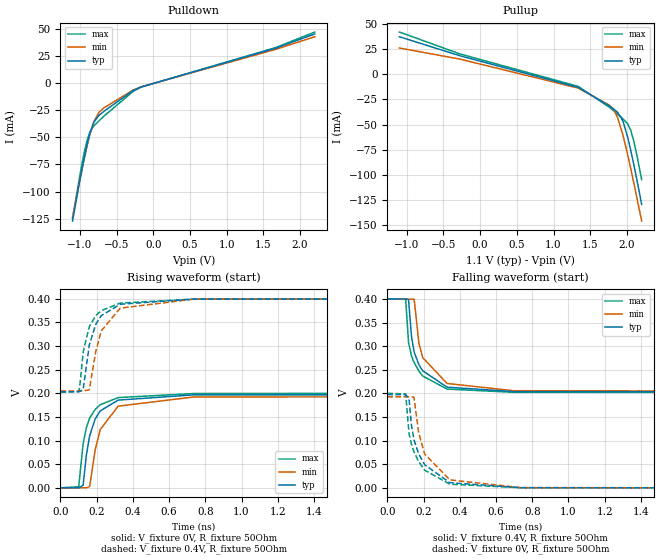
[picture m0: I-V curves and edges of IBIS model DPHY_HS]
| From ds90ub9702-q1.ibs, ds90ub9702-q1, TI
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|  DPHY_HS Tx Model
[Model]   DPHY_HS
Model_type   Output
Polarity   Non-Inverting
Vmeas = 0.2
Vref = 0.2
Cref = 1pF
Rref = 50
|   typ   min   max
C_comp   2.65pF   2.56pF   2.78pF
[Voltage Range]   1.1   1.045   1.155
[Temperature Range]   27   105   -40
[Pullup Reference]   1.1   1.045   1.155
[Pulldown Reference]   0   -0   0
[Power Clamp Reference]   1.1   1.045   1.155
[GND Clamp Reference]   0   0   0
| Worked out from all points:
|   slope of the pulldown table from 0 to 0.165 V, typ, clamps not added: 51.7 ohm
|   slope of the pullup table from 0 to 0.165 V, typ, clamps not added: 52.5 ohm
|   falling waveform, V_fixture 0.4V, R_fixture 50Ohm: 20-80 % time 79.1ps typ, 85.4ps min, 77.5ps max; typ from 0.4 V to 0.204 V
|   rising waveform, V_fixture 0V, R_fixture 50Ohm: 20-80 % time 75.7ps typ, 86ps min, 69.6ps max; typ from 0 V to 0.197 V
|   rising waveform, V_fixture 0.4V, R_fixture 50Ohm: 20-80 % time 81.7ps typ, 90.4ps min, 74.3ps max; typ from 0.204 V to 0.4 V
|   falling waveform, V_fixture 0V, R_fixture 50Ohm: 20-80 % time 98.2ps typ, 101ps min, 92.3ps max; typ from 0.197 V to 0 V
[Pulldown]
|   Voltage   I(typ)   I(min)   I(max)
-1.1V     -127.2mA   -123.8mA   -124.9mA
-994.4mV  -87.45mA   -86.96mA   -82.68mA
-948.2mV  -71.4mA    -71.86mA   -66.26mA
-902mV    -56.72mA   -57.79mA   -52.58mA
-862.4mV  -45.97mA   -47mA      -44.71mA
-809.6mV  -35.93mA   -35.5mA    -39.38mA
-740.3mV  -29.76mA   -26.9mA    -34.72mA
-674.3mV  -26.03mA   -22.85mA   -30.52mA
-275mV    -6.806mA   -6.299mA   -7.514mA
-169.4mV  -3.519mA   -3.433mA   -3.633mA
1.669V    32.36mA    31.28mA    32.93mA
2.2V      45.51mA    42.93mA    47.25mA
[Pullup]
|   Voltage   I(typ)   I(min)   I(max)
-1.1V     37.66mA    26.43mA    42.38mA
-275mV    18.65mA    15.32mA    20.51mA
1.335V    -12.88mA   -13.6mA    -11.92mA
1.761V    -31.45mA   -30.67mA   -32.76mA
1.824V    -34.77mA   -35.68mA   -36.61mA
1.873V    -37.83mA   -43.23mA   -39.69mA
1.946V    -46.7mA    -60.8mA    -44.3mA
2.012V    -63.19mA   -80.84mA   -49.56mA
2.051V    -75.66mA   -93.88mA   -55.78mA
2.091V    -89.21mA   -107.4mA   -65.99mA
2.137V    -105.9mA   -123.7mA   -81.3mA
2.2V      -129.8mA   -146.4mA   -105mA
[Ramp]
R_load = 50
|   typ   min   max
dV/dt_r   0.1183/7.52153e-11   0.115636/8.53108e-11   0.120039/6.91429e-11
dV/dt_f   0.117884/7.91703e-11   0.116867/8.53635e-11   0.118798/7.75972e-11
[Falling Waveform]
V_fixture = 0.4V
V_fixture_min = 0.4V
V_fixture_max = 0.4V
R_fixture = 50Ohm
C_fixture = 0F
|   Time   V(typ)   V(min)   V(max)
0s        400mV      399.9mV    400mV
101.3ps   400.1mV    399.6mV    399mV
117.2ps   398.5mV    399.5mV    307.6mV
133.2ps   321.8mV    399.5mV    279.7mV
148.1ps   287.7mV    399.4mV    265.2mV
174.2ps   260.8mV    307.1mV    247.4mV
195.2ps   247.9mV    275.8mV    236.9mV
330ps     213.2mV    221mV      209.1mV
699.5ps   203.8mV    205.6mV    202.3mV
2.4ns     203.5mV    205.1mV    202mV
[Rising Waveform]
V_fixture = 0V
V_fixture_min = 0V
V_fixture_max = 0V
R_fixture = 50Ohm
C_fixture = 0F
|   Time   V(typ)   V(min)   V(max)
0s        42.39uV    84.89uV    57.16uV
100.8ps   -37.34uV   25.25uV    2.25mV
124.9ps   5.327mV    10.96uV    92.54mV
143.4ps   70.35mV    21.21uV    128.1mV
161.3ps   110.2mV    2.749mV    147.7mV
192.1ps   146mV      81.23mV    166.1mV
220.3ps   163.1mV    123.8mV    176mV
318.8ps   185.7mV    172.9mV    191mV
735.6ps   196.8mV    192.3mV    199.6mV
2.4ns     197.2mV    192.8mV    200.1mV
[Rising Waveform]
V_fixture = 0.4V
V_fixture_min = 0.4V
V_fixture_max = 0.4V
R_fixture = 50Ohm
C_fixture = 0F
|   Time   V(typ)   V(min)   V(max)
0s        203.5mV    205.1mV    202mV
100.4ps   203.5mV    205.1mV    204mV
105.7ps   203.5mV    205.1mV    211.3mV
125.8ps   209.3mV    205.1mV    288.1mV
159.1ps   302.2mV    207.5mV    341.2mV
195.2ps   346.4mV    289mV      364.6mV
225.6ps   364.6mV    332.2mV    375.1mV
330ps     388.6mV    380.4mV    391.1mV
735.6ps   399.6mV    399.4mV    399.5mV
2.4ns     400mV      399.9mV    400mV
[Falling Waveform]
|Gnd
V_fixture = 0V
V_fixture_min = 0V
V_fixture_max = 0V
R_fixture = 50Ohm
C_fixture = 0F
|   Time   V(typ)   V(min)   V(max)
0s        197.2mV    192.8mV    200.1mV
101.3ps   197.3mV    192.9mV    198.8mV
120ps     188.2mV    192.9mV    114.7mV
132.5ps   134.8mV    192.8mV    93.33mV
147ps     102.3mV    191.8mV    76.54mV
173.1ps   72.02mV    116.9mV    55.43mV
206.4ps   48.85mV    71.5mV     37.43mV
344.9ps   11.07mV    16.96mV    7.82mV
735.6ps   346.2uV    498.3uV    314.1uV
2.4ns     42.48uV    84.94uV    57.48uV
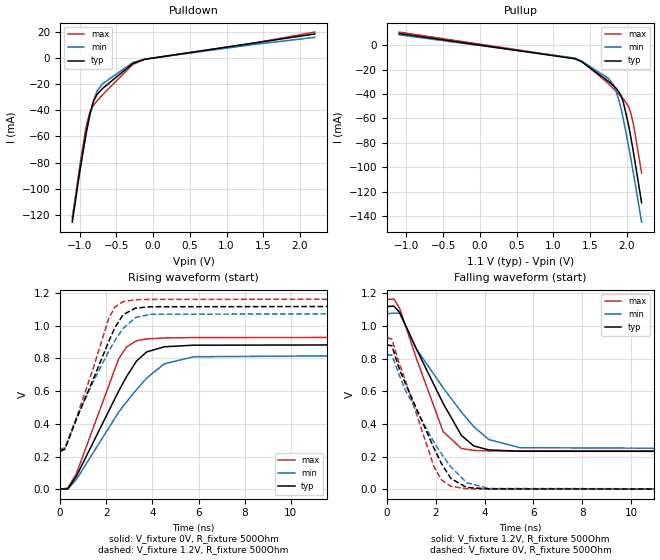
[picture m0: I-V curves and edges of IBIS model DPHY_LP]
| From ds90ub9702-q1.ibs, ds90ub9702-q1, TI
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|  DPHY_LP Tx Model - note: the diff cell line in IBIS needs to be commented out to use this model
[Model]   DPHY_LP
Model_type   Output
Polarity   Non-Inverting
Vmeas = 0.5
Vref = 0
Cref = 1pF
Rref = 100000
|   typ   min   max
C_comp   2.65pF   2.56pF   2.78pF
[Voltage Range]   1.1   1.045   1.155
[Temperature Range]   27   105   -40
[Pullup Reference]   1.1   1.045   1.155
[Pulldown Reference]   0   -0   0
[Power Clamp Reference]   1.1   1.045   1.155
[GND Clamp Reference]   0   0   0
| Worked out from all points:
|   slope of the pulldown table from 0 to 0.165 V, typ, clamps not added: 119 ohm
|   slope of the pullup table from 0 to 0.165 V, typ, clamps not added: 122 ohm
|   falling waveform, V_fixture 1.2V, R_fixture 500Ohm: 20-80 % time 1.75ns typ, 2.37ns min, 1.28ns max; typ from 1.12 V to 0.231 V
|   rising waveform, V_fixture 0V, R_fixture 500Ohm: 20-80 % time 1.9ns typ, 2.52ns min, 1.4ns max; typ from 0.001 V to 0.884 V
|   rising waveform, V_fixture 1.2V, R_fixture 500Ohm: 20-80 % time 1.58ns typ, 1.74ns min, 1.29ns max; typ from 0.231 V to 1.12 V
|   falling waveform, V_fixture 0V, R_fixture 500Ohm: 20-80 % time 1.58ns typ, 1.88ns min, 1.24ns max; typ from 0.884 V to 0 V
[Pulldown]
|   Voltage   I(typ)   I(min)   I(max)
-1.1V     -125.5mA   -121.7mA   -123.4mA
-1.001V   -87.99mA   -86.97mA   -83.51mA
-921.8mV  -60.72mA   -61.25mA   -55.86mA
-898.7mV  -53.56mA   -54.33mA   -49.38mA
-859.1mV  -42.68mA   -43.44mA   -41.28mA
-809.6mV  -32.88mA   -32.35mA   -36.08mA
-763.4mV  -27.93mA   -25.44mA   -32.9mA
-690.8mV  -23.5mA    -19.88mA   -28.31mA
-275mV    -4.189mA   -3.529mA   -4.903mA
-113.3mV  -999.2uA   -940.8uA   -984.4uA
1.378V    11.41mA    10.32mA    11.42mA
2.2V      18.3mA     15.72mA    19.75mA
[Pullup]
|   Voltage   I(typ)   I(min)   I(max)
-1.1V     9.521mA    8.451mA    10.71mA
1.289V    -11.12mA   -10.54mA   -10.81mA
1.382V    -13.51mA   -12.89mA   -12.95mA
1.745V    -29.44mA   -27.08mA   -31.27mA
1.807V    -32.64mA   -31.41mA   -35.04mA
1.853V    -35.22mA   -37.41mA   -37.86mA
1.913V    -40.35mA   -50.07mA   -41.54mA
1.952V    -46.95mA   -60.87mA   -44.07mA
2.022V    -65.33mA   -82.39mA   -50.11mA
2.058V    -77.06mA   -94.5mA    -56.67mA
2.094V    -89.62mA   -107mA     -66.53mA
2.2V      -129.1mA   -144.9mA   -104.7mA
[Ramp]
R_load = 500
|   typ   min   max
dV/dt_r   0.53021/1.89738e-09   0.493046/2.51787e-09   0.557075/1.40277e-09
dV/dt_f   0.53254/1.74597e-09   0.497476/2.36272e-09   0.558185/1.28049e-09
[Falling Waveform]
V_fixture = 1.2V
V_fixture_min = 1.2V
V_fixture_max = 1.2V
R_fixture = 500Ohm
C_fixture = 0F
|   Time   V(typ)   V(min)   V(max)
0s        1.119V     1.075V     1.163V
281.7ps   1.122V     1.079V     1.165V
518.8ps   1.083V     1.078V     1.107V
1.193ns   862.2mV    861.7mV    805mV
2.298ns   525.8mV    621.2mV    353.3mV
3.046ns   329.7mV    472.5mV    249.2mV
3.552ns   264.9mV    383.5mV    237.6mV
4.172ns   240.5mV    303.7mV    234.5mV
5.464ns   232.3mV    254.1mV    233.6mV
20ns      231.3mV    246.1mV    233mV
[Rising Waveform]
V_fixture = 0V
V_fixture_min = 0V
V_fixture_max = 0V
R_fixture = 500Ohm
C_fixture = 0F
|   Time   V(typ)   V(min)   V(max)
0s        576.5uV    1.061mV    749.3uV
330.7ps   2.593mV    927.1uV    7.834mV
702.7ps   79.42mV    59.54mV    95.17mV
2.536ns   600.4mV    471.5mV    797.7mV
2.877ns   688.8mV    534mV      869.9mV
3.308ns   783.9mV    608.9mV    908mV
3.746ns   839.6mV    679.8mV    919.4mV
4.511ns   871.2mV    766.6mV    925.2mV
5.78ns    880.9mV    810.3mV    927.5mV
20ns      884.3mV    822.8mV    929.2mV
[Rising Waveform]
V_fixture = 1.2V
V_fixture_min = 1.2V
V_fixture_max = 1.2V
R_fixture = 500Ohm
C_fixture = 0F
|   Time   V(typ)   V(min)   V(max)
0s        231.4mV    246mV      233.2mV
204.9ps   245.2mV    251.9mV    250.6mV
732.1ps   438.1mV    445.7mV    447.4mV
1.399ns   660.6mV    648.4mV    724.7mV
2.109ns   904.7mV    844.9mV    1.047V
2.375ns   989.1mV    909.2mV    1.114V
2.726ns   1.067V     982.7mV    1.147V
3.264ns   1.108V     1.05V      1.159V
3.929ns   1.116V     1.07V      1.161V
20ns      1.119V     1.075V     1.163V
[Falling Waveform]
|Gnd
V_fixture = 0V
V_fixture_min = 0V
V_fixture_max = 0V
R_fixture = 500Ohm
C_fixture = 0F
|   Time   V(typ)   V(min)   V(max)
0s        884.1mV    823.3mV    929.1mV
198.7ps   879mV      822.2mV    919.3mV
513.8ps   732.2mV    694.1mV    764mV
755.1ps   646.6mV    605.2mV    664.7mV
1.921ns   251.9mV    287.8mV    138.9mV
2.222ns   159.4mV    219mV      58.56mV
2.621ns   65.01mV    135.4mV    17.12mV
3.264ns   10.54mV    39.25mV    2.988mV
4.172ns   1.646mV    4.311mV    648.1uV
20ns      110.5uV    155.6uV    234.3uV
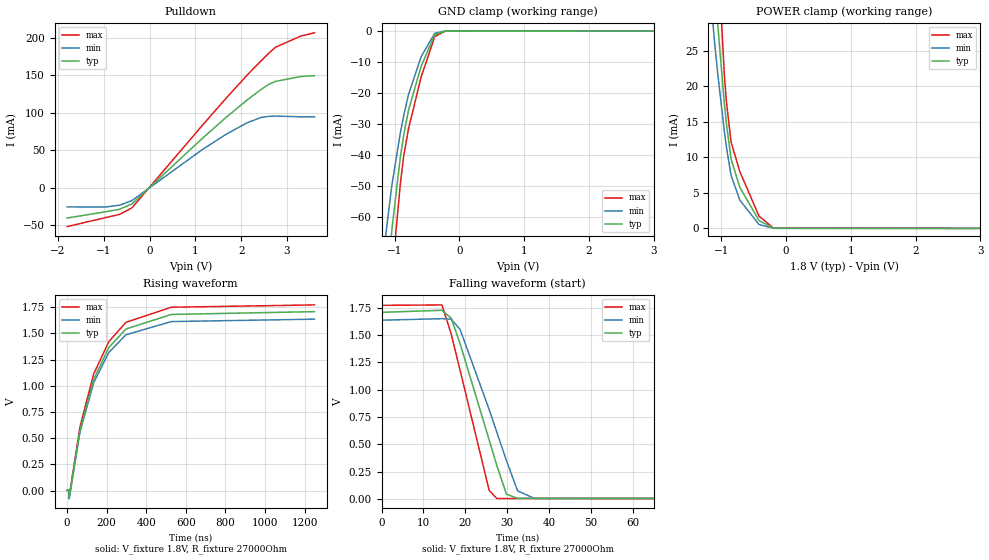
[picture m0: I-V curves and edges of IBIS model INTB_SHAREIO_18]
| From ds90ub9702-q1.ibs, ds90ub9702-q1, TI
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| INTB_SHAREIO_18
[Model]   INTB_SHAREIO_18
Model_type   I/O_open_drain
Polarity   Non-Inverting
Enable   Active-High
Vinl = 0.54
Vinh = 1.26
Vmeas = 0.9
Vref = 1.8
Cref = 0pF
Rref = 27000
|   typ   min   max
C_comp   2.908307pF   2.652408pF   3.339183pF
[Voltage Range]   1.8   1.71   1.89
[Temperature Range]   27   105   -40
[Pullup Reference]   1.8   1.71   1.89
[Pulldown Reference]   0   0   0
[Power Clamp Reference]   1.8   1.71   1.89
[GND Clamp Reference]   0   0   0
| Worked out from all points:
|   slope of the pulldown table from 0 to 0.27 V, typ, clamps not added: 17.2 ohm
|   GND clamp passes 1 mA (typ) near -0.37 V on its own axis
|   POWER clamp passes 1 mA (typ) near -0.41 V on its own axis
|   falling waveform, V_fixture 1.8V, R_fixture 27000Ohm: 20-80 % time 8.03ns typ, 8.75ns min, 6.68ns max; typ from 1.71 V to 0.001 V
|   rising waveform, V_fixture 1.8V, R_fixture 27000Ohm: 20-80 % time 169ns typ, 165ns min, 168ns max; typ from 0.001 V to 1.71 V
[Pulldown]
|   Voltage   I(typ)   I(min)   I(max)
-1.8V     -40.81mA   -25.92mA   -52.24mA
-963mV    -32.45mA   -26.08mA   -40.24mA
-655.2mV  -29.11mA   -23.61mA   -35.97mA
-385.2mV  -21.86mA   -17.45mA   -27.16mA
1.143V    65.23mA    50.4mA     82.48mA
1.672V    93.87mA    71.29mA    119.5mA
2.126V    116.9mA    86.51mA    150.1mA
2.434V    131.1mA    93.69mA    169.4mA
2.59V     137.6mA    95.11mA    178.9mA
2.747V    141.9mA    95.56mA    187.5mA
3.303V    148.5mA    94.53mA    202.6mA
3.6V      149.6mA    94.59mA    206.9mA
[GND Clamp]
|   Voltage   I(typ)   I(min)   I(max)
-1.8V     -237.8mA   -203.7mA   -280.5mA
-1.201V   -98.67mA   -77.69mA   -120.2mA
-1.141V   -85.44mA   -66.63mA   -104.6mA
-1.06V    -68.06mA   -52.8mA    -83.81mA
-1.033V   -62.53mA   -48.63mA   -77.07mA
-909mV    -40.42mA   -32.65mA   -48.95mA
-855mV    -33.13mA   -26.94mA   -39.78mA
-784.8mV  -25.61mA   -20.52mA   -31.59mA
-590.4mV  -11.4mA    -8.304mA   -14.89mA
-379.8mV  -1.192mA   -722uA     -1.803mA
-217.8mV  -11.59uA   -13.02uA   -8.077uA
3.6V      0A         0A         0A
[POWER Clamp]
|   Voltage   I(typ)   I(min)   I(max)
-1.8V     189.5mA    145.7mA    235.2mA
-1.244V   62.47mA    42.38mA    84.9mA
-1.168V   47.33mA    32.73mA    65.73mA
-1.098V   34.96mA    25.57mA    48.82mA
-1.055V   28.63mA    21.7mA     39.2mA
-952.2mV  17.42mA    13.54mA    21.38mA
-919.8mV  14.61mA    11.31mA    17.64mA
-849.6mV  9.773mA    7.445mA    12.14mA
-714.6mV  5.771mA    3.976mA    7.99mA
-417.6mV  1.093mA    537.9uA    1.718mA
-190.8mV  15.57uA    9.205uA    20.28uA
3.6V      0A         0A         0A
[Ramp]
R_load = 27000
|   typ   min   max
dV/dt_r   1.024/1.6938e-07   0.980528/1.65356e-07   1.06284/1.68482e-07
dV/dt_f   1.024/8.02563e-09   0.980528/8.74431e-09   1.06284/6.67672e-09
[Falling Waveform]
V_fixture = 1.8V
V_fixture_min = 1.71V
V_fixture_max = 1.89V
R_fixture = 27000Ohm
C_fixture = 0F
|   Time   V(typ)   V(min)   V(max)
0s        1.708V     1.636V     1.772V
14.41ns   1.727V     1.65V      1.776V
16.61ns   1.655V     1.645V     1.511V
18.72ns   1.424V     1.553V     1.18V
25.69ns   538mV      816.6mV    75.99mV
27.49ns   307.1mV    613.1mV    3.091mV
29.8ns    42.54mV    350mV      2.74mV
32.47ns   3.684mV    72.42mV    2.638mV
36.45ns   3.486mV    4.349mV    2.485mV
1.25us    1.14mV     1.372mV    954.9uV
[Rising Waveform]
V_fixture = 1.8V
V_fixture_min = 1.71V
V_fixture_max = 1.89V
R_fixture = 27000Ohm
C_fixture = 0F
|   Time   V(typ)   V(min)   V(max)
0s        1.14mV     1.372mV    954.9uV
10.16ns   1.231mV    1.479mV    1.026mV
10.31ns   -21.29mV   -4.848mV   -76.36mV
10.53ns   -66.44mV   -77.94mV   -54.06mV
64.5ns    573.8mV    554.8mV    604.5mV
133.8ns   1.06V      1.027V     1.112V
210.5ns   1.365V     1.318V     1.421V
297.2ns   1.542V     1.487V     1.606V
526.6ns   1.681V     1.613V     1.75V
1.25us    1.708V     1.636V     1.772V
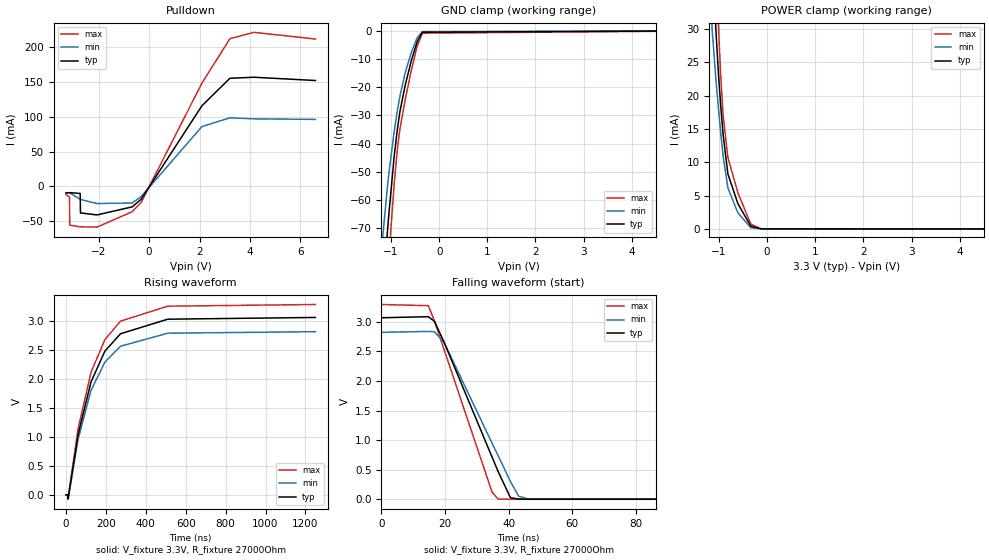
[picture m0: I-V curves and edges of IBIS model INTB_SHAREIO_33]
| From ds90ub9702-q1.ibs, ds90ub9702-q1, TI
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| INTB_SHAREIO_33
[Model]   INTB_SHAREIO_33
Model_type   I/O_open_drain
Polarity   Non-Inverting
Enable   Active-High
Vinl = 0.99
Vinh = 2.31
Vmeas = 1.65
Vref = 3.3
Cref = 0pF
Rref = 27000
|   typ   min   max
C_comp   2.908307pF   2.652408pF   3.339183pF
[Voltage Range]   3.3   3   3.6
[Temperature Range]   27   105   -40
[Pullup Reference]   3.3   3   3.6
[Pulldown Reference]   -0   -0   0
[Power Clamp Reference]   3.3   3   3.6
[GND Clamp Reference]   0   0   0
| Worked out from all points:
|   slope of the pulldown table from 0 to 0.495 V, typ, clamps not added: 17.3 ohm
|   GND clamp passes 1 mA (typ) near -0.37 V on its own axis
|   POWER clamp passes 1 mA (typ) near -0.41 V on its own axis
|   falling waveform, V_fixture 3.3V, R_fixture 27000Ohm: 20-80 % time 14.3ns typ, 14.9ns min, 12.3ns max; typ from 3.07 V to 0.002 V
|   rising waveform, V_fixture 3.3V, R_fixture 27000Ohm: 20-80 % time 151ns typ, 150ns min, 150ns max; typ from 0.002 V to 3.07 V
[Pulldown]
|   Voltage   I(typ)   I(min)   I(max)
-3.3V     -9.272mA   -9.512mA   -11.91mA
-3.161V   -9.003mA   -9.27mA    -15.22mA
-3.151V   -8.987mA   -9.256mA   -55.69mA
-2.736V   -10.16mA   -18.57mA   -57.93mA
-2.726V   -38.08mA   -18.76mA   -57.97mA
-2.072V   -40.96mA   -24.59mA   -58.48mA
-676.5mV  -29.45mA   -23.87mA   -36.41mA
-320.1mV  -18.58mA   -14.72mA   -23.24mA
2.095V    115.6mA    85.71mA    148.1mA
3.204V    155mA      98.28mA    211.7mA
4.155V    156.5mA    96.84mA    220.9mA
6.6V      151.8mA    96.02mA    211.3mA
[GND Clamp]
|   Voltage   I(typ)   I(min)   I(max)
-3.3V     -615.5mA   -541.1mA   -700.9mA
-1.211V   -101mA     -79.7mA    -123mA
-1.073V   -70.63mA   -54.78mA   -86.92mA
-1.043V   -64.48mA   -50.08mA   -79.46mA
-933.9mV  -44.27mA   -35.5mA    -54mA
-864.6mV  -34.33mA   -27.91mA   -41.22mA
-815.1mV  -28.59mA   -23.13mA   -34.72mA
-706.2mV  -19.3mA    -14.93mA   -24.48mA
-577.5mV  -10.58mA   -7.646mA   -13.88mA
-458.7mV  -3.987mA   -2.568mA   -5.598mA
-349.8mV  -621.2uA   -387.2uA   -936.6uA
6.6V      0A         0A         0A
[POWER Clamp]
|   Voltage   I(typ)   I(min)   I(max)
-3.3V     554.7mA    458.8mA    658.7mA
-1.142V   42.43mA    29.87mA    59.25mA
-1.063V   29.69mA    22.38mA    40.88mA
-1.013V   23.54mA    18.22mA    30.89mA
-1.003V   22.46mA    17.42mA    29.11mA
-963.6mV  18.48mA    14.37mA    22.91mA
-914.1mV  14.15mA    10.94mA    17.07mA
-815.1mV  8.256mA    6.171mA    10.73mA
-607.2mV  3.804mA    2.414mA    5.429mA
-339.9mV  429uA      182.1uA    727.7uA
-122.1mV  10.85uA    8.314uA    13.88uA
6.6V      0A         0A         0A
[Ramp]
R_load = 27000
|   typ   min   max
dV/dt_r   1.84002/1.51055e-07   1.69213/1.4849e-07   1.9748/1.48829e-07
dV/dt_f   1.84002/1.43251e-08   1.69213/1.49247e-08   1.9748/1.23376e-08
[Falling Waveform]
V_fixture = 3.3V
V_fixture_min = 3V
V_fixture_max = 3.6V
R_fixture = 27000Ohm
C_fixture = 0F
|   Time   V(typ)   V(min)   V(max)
0s        3.069V     2.823V     3.293V
14.75ns   3.087V     2.838V     3.273V
16.69ns   3.007V     2.83V      3.014V
19.69ns   2.657V     2.653V     2.533V
34.77ns   718.8mV    952.5mV    125.9mV
36.74ns   466.8mV    735.7mV    5.5mV
40.56ns   30.35mV    304mV      3.634mV
43.15ns   5.857mV    53.09mV    2.586mV
46.27ns   4.62mV     7.523mV    2.397mV
1.25us    2.119mV    2.437mV    1.85mV
[Rising Waveform]
V_fixture = 3.3V
V_fixture_min = 3V
V_fixture_max = 3.6V
R_fixture = 27000Ohm
C_fixture = 0F
|   Time   V(typ)   V(min)   V(max)
0s        2.119mV    2.437mV    1.85mV
10.16ns   2.211mV    2.544mV    1.922mV
10.31ns   -20.26mV   -3.786mV   -74.77mV
10.52ns   -64.64mV   -75.83mV   -54.04mV
60.78ns   1.048V     966.4mV    1.148V
125.9ns   1.959V     1.814V     2.126V
195ns     2.487V     2.297V     2.686V
273.1ns   2.787V     2.571V     3.005V
509.8ns   3.039V     2.797V     3.264V
1.25us    3.069V     2.823V     3.293V
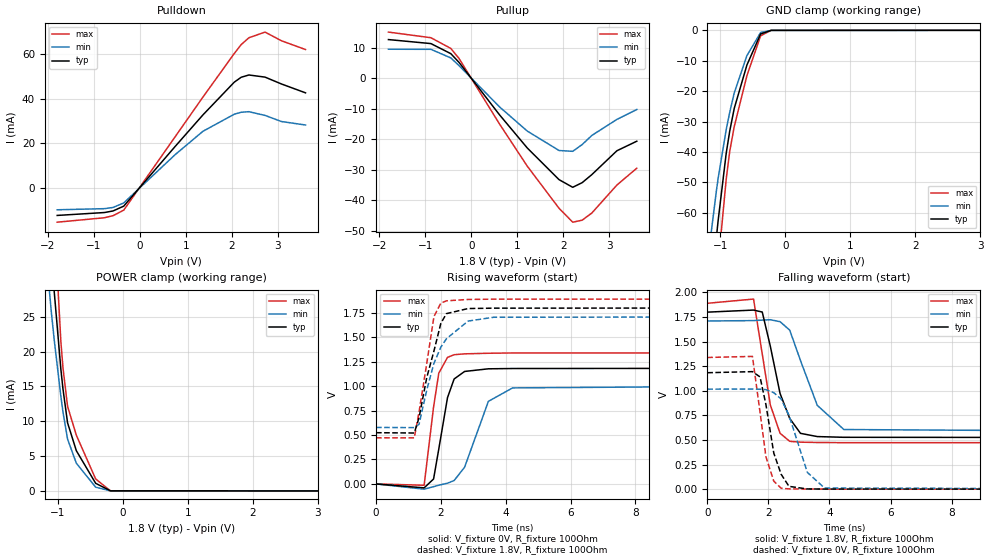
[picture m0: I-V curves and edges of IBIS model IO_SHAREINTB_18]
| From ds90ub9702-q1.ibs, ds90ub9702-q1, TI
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| IO_SHAREINTB_18
[Model]   IO_SHAREINTB_18
Model_type   I/O
Polarity   Non-Inverting
Enable   Active-High
Vinl = 0.63
Vinh = 1.17
Vmeas = 0.9
Vref = 0
Cref = 0pF
Rref = 100000
|   typ   min   max
C_comp   2.419024pF   2.419024pF   2.53303pF
[Voltage Range]   1.8   1.71   1.89
[Temperature Range]   27   105   -40
[Pullup Reference]   1.8   1.71   1.89
[Pulldown Reference]   0   0   0
[Power Clamp Reference]   1.8   1.71   1.89
[GND Clamp Reference]   0   0   0
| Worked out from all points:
|   slope of the pulldown table from 0 to 0.27 V, typ, clamps not added: 40.9 ohm
|   slope of the pullup table from 0 to 0.27 V, typ, clamps not added: 50.8 ohm
|   GND clamp passes 1 mA (typ) near -0.37 V on its own axis
|   POWER clamp passes 1 mA (typ) near -0.41 V on its own axis
|   falling waveform, V_fixture 1.8V, R_fixture 100Ohm: 20-80 % time 604ps typ, 824ps min, 449ps max; typ from 1.8 V to 0.524 V
|   rising waveform, V_fixture 0V, R_fixture 100Ohm: 20-80 % time 371ps typ, 647ps min, 282ps max; typ from 0 V to 1.18 V
|   rising waveform, V_fixture 1.8V, R_fixture 100Ohm: 20-80 % time 536ps typ, 706ps min, 389ps max; typ from 0.524 V to 1.8 V
|   falling waveform, V_fixture 0V, R_fixture 100Ohm: 20-80 % time 429ps typ, 617ps min, 339ps max; typ from 1.18 V to 0 V
[Pulldown]
|   Voltage   I(typ)   I(min)   I(max)
-1.8V     -12.52mA   -9.972mA   -15.56mA
-774mV    -11.21mA   -9.467mA   -13.56mA
-585mV    -10.5mA    -8.919mA   -12.62mA
-352.8mV  -8.323mA   -6.883mA   -10.13mA
765mV     18.56mA    14.87mA    22.93mA
1.37V     32.79mA    25.4mA     40.82mA
2.05V     47.51mA    33.08mA    60.42mA
2.201V    49.73mA    33.97mA    64.44mA
2.369V    50.76mA    34.22mA    67.53mA
2.72V     49.79mA    32.54mA    70.08mA
3.076V    46.71mA    29.79mA    66.17mA
3.6V      42.71mA    28.22mA    62.22mA
[GND Clamp]
|   Voltage   I(typ)   I(min)   I(max)
-1.8V     -237.8mA   -203.7mA   -280.5mA
-1.201V   -98.67mA   -77.69mA   -120.2mA
-1.141V   -85.44mA   -66.63mA   -104.6mA
-1.06V    -68.06mA   -52.8mA    -83.81mA
-1.033V   -62.53mA   -48.63mA   -77.07mA
-909mV    -40.42mA   -32.65mA   -48.95mA
-855mV    -33.13mA   -26.94mA   -39.78mA
-784.8mV  -25.61mA   -20.52mA   -31.59mA
-590.4mV  -11.4mA    -8.304mA   -14.89mA
-379.8mV  -1.192mA   -722uA     -1.803mA
-217.8mV  -11.59uA   -13.02uA   -8.077uA
3.6V      0A         0A         0A
[Pullup]
|   Voltage   I(typ)   I(min)   I(max)
-1.8V     12.78mA    9.604mA    15.24mA
-876.6mV  11.46mA    9.58mA     13.39mA
-444.6mV  8.159mA    6.753mA    9.877mA
-266.4mV  5.308mA    4.24mA     6.596mA
613.8mV   -11.92mA   -9.313mA   -14.93mA
1.219V    -22.85mA   -17.3mA    -28.83mA
1.91V     -33.26mA   -23.68mA   -42.68mA
2.207V    -35.77mA   -23.95mA   -47.24mA
2.412V    -34.25mA   -21.74mA   -46.59mA
2.623V    -31.6mA    -18.73mA   -44.22mA
3.168V    -23.76mA   -13.45mA   -35.03mA
3.6V      -20.63mA   -10.22mA   -29.5mA
[POWER Clamp]
|   Voltage   I(typ)   I(min)   I(max)
-1.8V     189.5mA    145.7mA    235.2mA
-1.244V   62.47mA    42.38mA    84.9mA
-1.168V   47.33mA    32.73mA    65.73mA
-1.098V   34.96mA    25.57mA    48.82mA
-1.055V   28.63mA    21.7mA     39.2mA
-952.2mV  17.42mA    13.54mA    21.38mA
-919.8mV  14.61mA    11.31mA    17.64mA
-849.6mV  9.773mA    7.445mA    12.14mA
-714.6mV  5.771mA    3.976mA    7.99mA
-417.6mV  1.093mA    537.9uA    1.718mA
-190.8mV  15.57uA    9.205uA    20.28uA
3.6V      0A         0A         0A
[Ramp]
R_load = 100
|   typ   min   max
dV/dt_r   0.710464/3.70417e-10   0.610072/6.43402e-10   0.803117/2.8188e-10
dV/dt_f   0.765474/5.98922e-10   0.679179/8.19152e-10   0.850695/4.47587e-10
[Falling Waveform]
V_fixture = 1.8V
V_fixture_min = 1.71V
V_fixture_max = 1.89V
R_fixture = 100Ohm
C_fixture = 0F
|   Time   V(typ)   V(min)   V(max)
0s        1.8V       1.71V      1.89V
1.515ns   1.821V     1.714V     1.933V
1.8ns     1.801V     1.719V     1.375V
2.064ns   1.454V     1.723V     856.7mV
2.383ns   973.4mV    1.703V     568.5mV
2.699ns   719.3mV    1.617V     486.6mV
3.052ns   567.6mV    1.308V     478mV
3.601ns   534.8mV    852.6mV    474.7mV
4.472ns   527.4mV    606.5mV    472.9mV
20ns      524mV      577.8mV    472mV
[Rising Waveform]
V_fixture = 0V
V_fixture_min = 0V
V_fixture_max = 0V
R_fixture = 100Ohm
C_fixture = 0F
|   Time   V(typ)   V(min)   V(max)
0s        53.86uV    50.52uV    52.96uV
1.484ns   -39.91mV   -53.38mV   -13.42mV
1.775ns   50.56mV    -27.81mV   786.6mV
1.935ns   355.4mV    -12.87mV   1.132V
2.205ns   882.4mV    7.675mV    1.294V
2.409ns   1.073V     34.83mV    1.321V
2.732ns   1.15V      171.2mV    1.33V
3.466ns   1.177V     844.4mV    1.336V
4.213ns   1.18V      981.9mV    1.339V
20ns      1.184V     1.017V     1.339V
[Rising Waveform]
V_fixture = 1.8V
V_fixture_min = 1.71V
V_fixture_max = 1.89V
R_fixture = 100Ohm
C_fixture = 0F
|   Time   V(typ)   V(min)   V(max)
0s        524mV      577.8mV    472mV
1.18ns    520.7mV    575.5mV    470.8mV
1.327ns   678.2mV    609.5mV    735.8mV
1.565ns   1.088V     960.3mV    1.231V
1.785ns   1.357V     1.232V     1.71V
1.999ns   1.641V     1.399V     1.848V
2.171ns   1.741V     1.484V     1.872V
2.839ns   1.793V     1.665V     1.886V
3.626ns   1.797V     1.704V     1.889V
20ns      1.8V       1.71V      1.89V
[Falling Waveform]
|Gnd
V_fixture = 0V
V_fixture_min = 0V
V_fixture_max = 0V
R_fixture = 100Ohm
C_fixture = 0F
|   Time   V(typ)   V(min)   V(max)
0s        1.184V     1.017V     1.339V
1.479ns   1.195V     1.018V     1.35V
1.728ns   1.141V     1.016V     782.2mV
1.921ns   858.8mV    1.012V     328mV
2.178ns   366.5mV    981mV      81.22mV
2.419ns   151.4mV    916.6mV    9.287mV
2.675ns   28.51mV    751.7mV    2.87mV
3.276ns   2.349mV    170.8mV    1.376mV
3.84ns    1.193mV    11.19mV    736.5uV
20ns      63.28uV    65.8uV     58.41uV
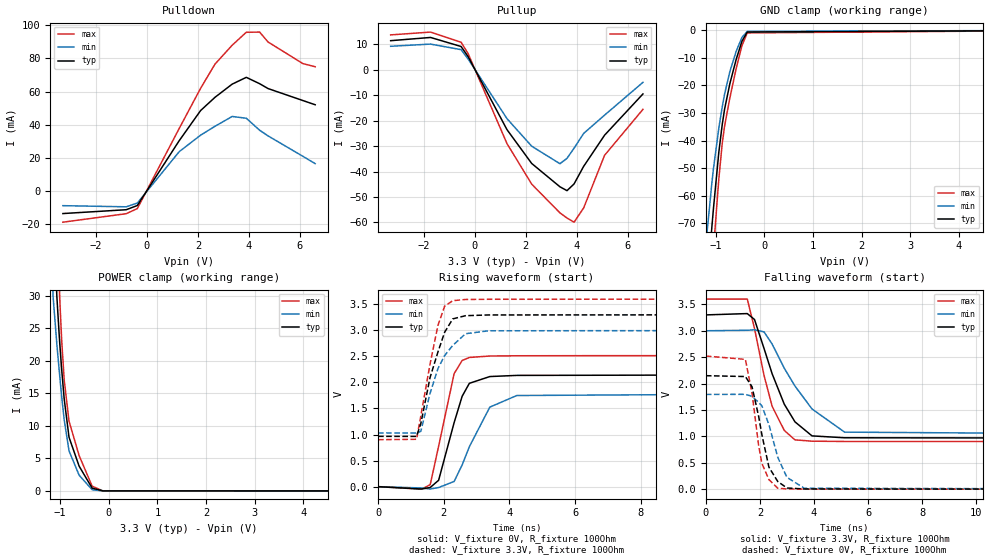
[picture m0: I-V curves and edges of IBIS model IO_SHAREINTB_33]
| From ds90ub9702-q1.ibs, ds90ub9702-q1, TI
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| IO_SHAREINTB_33
[Model]   IO_SHAREINTB_33
Model_type   I/O
Polarity   Non-Inverting
Enable   Active-High
Vinl = 1.155
Vinh = 2.145
Vmeas = 1.65
Vref = 0
Cref = 0pF
Rref = 100000
|   typ   min   max
C_comp   2.31015pF   2.419024pF   2.419024pF
[Voltage Range]   3.3   3   3.6
[Temperature Range]   27   105   -40
[Pullup Reference]   3.3   3   3.6
[Pulldown Reference]   0   0   -0
[Power Clamp Reference]   3.3   3   3.6
[GND Clamp Reference]   0   0   0
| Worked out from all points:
|   slope of the pulldown table from 0 to 0.495 V, typ, clamps not added: 41.1 ohm
|   slope of the pullup table from 0 to 0.495 V, typ, clamps not added: 51.4 ohm
|   GND clamp passes 1 mA (typ) near -0.37 V on its own axis
|   POWER clamp passes 1 mA (typ) near -0.41 V on its own axis
|   falling waveform, V_fixture 3.3V, R_fixture 100Ohm: 20-80 % time 1.03ns typ, 1.5ns min, 753ps max; typ from 3.3 V to 0.966 V
|   rising waveform, V_fixture 0V, R_fixture 100Ohm: 20-80 % time 572ps typ, 790ps min, 488ps max; typ from 0 V to 2.15 V
|   rising waveform, V_fixture 3.3V, R_fixture 100Ohm: 20-80 % time 581ps typ, 679ps min, 488ps max; typ from 0.966 V to 3.3 V
|   falling waveform, V_fixture 0V, R_fixture 100Ohm: 20-80 % time 504ps typ, 640ps min, 413ps max; typ from 2.15 V to 0 V
[Pulldown]
|   Voltage   I(typ)   I(min)   I(max)
-3.3V     -13.6mA    -8.838mA   -18.81mA
-815.1mV  -11.29mA   -9.531mA   -13.68mA
-379.5mV  -8.752mA   -7.281mA   -10.61mA
1.264V    30.34mA    23.72mA    37.71mA
2.105V    48.54mA    33.69mA    61.97mA
2.67V     56.53mA    39.04mA    76.56mA
3.343V    64.46mA    44.96mA    87.93mA
3.897V    68.55mA    43.88mA    95.74mA
4.422V    64.71mA    36.64mA    95.85mA
4.749V    61.8mA     33.26mA    89.89mA
6.115V    54.58mA    20.95mA    76.87mA
6.6V      52.02mA    16.51mA    74.95mA
[GND Clamp]
|   Voltage   I(typ)   I(min)   I(max)
-3.3V     -615.5mA   -541.1mA   -700.9mA
-1.211V   -101mA     -79.7mA    -123mA
-1.073V   -70.63mA   -54.78mA   -86.92mA
-1.043V   -64.48mA   -50.08mA   -79.46mA
-933.9mV  -44.27mA   -35.5mA    -54mA
-864.6mV  -34.33mA   -27.91mA   -41.22mA
-815.1mV  -28.59mA   -23.13mA   -34.72mA
-706.2mV  -19.3mA    -14.93mA   -24.48mA
-577.5mV  -10.58mA   -7.646mA   -13.88mA
-458.7mV  -3.987mA   -2.568mA   -5.598mA
-349.8mV  -621.2uA   -387.2uA   -936.6uA
6.6V      0A         0A         0A
[Pullup]
|   Voltage   I(typ)   I(min)   I(max)
-3.3V     11.47mA    9.265mA    13.75mA
-1.736V   12.74mA    10.13mA    14.85mA
-537.9mV  9.183mA    7.947mA    10.87mA
-260.7mV  5.188mA    4.269mA    6.391mA
1.264V    -23.52mA   -19.2mA    -29.01mA
2.234V    -36.83mA   -30.04mA   -44.96mA
3.343V    -46.01mA   -36.93mA   -56.27mA
3.62V     -47.52mA   -34.8mA    -58.29mA
3.897V    -44.87mA   -30.81mA   -59.93mA
4.274V    -37.95mA   -24.99mA   -54.3mA
5.095V    -25.7mA    -17.81mA   -33.61mA
6.6V      -9.486mA   -4.913mA   -15.54mA
[POWER Clamp]
|   Voltage   I(typ)   I(min)   I(max)
-3.3V     554.7mA    458.8mA    658.7mA
-1.142V   42.43mA    29.87mA    59.25mA
-1.063V   29.69mA    22.38mA    40.88mA
-1.013V   23.54mA    18.22mA    30.89mA
-1.003V   22.46mA    17.42mA    29.11mA
-963.6mV  18.48mA    14.37mA    22.91mA
-914.1mV  14.15mA    10.94mA    17.07mA
-815.1mV  8.256mA    6.171mA    10.73mA
-607.2mV  3.804mA    2.414mA    5.429mA
-339.9mV  429uA      182.1uA    727.7uA
-122.1mV  10.85uA    8.314uA    13.88uA
6.6V      0A         0A         0A
[Ramp]
R_load = 100
|   typ   min   max
dV/dt_r   1.29235/5.70997e-10   1.08278/7.83434e-10   1.51359/4.87014e-10
dV/dt_f   1.40025/1.03057e-09   1.18203/1.49926e-09   1.61896/7.521e-10
[Falling Waveform]
V_fixture = 3.3V
V_fixture_min = 3V
V_fixture_max = 3.6V
R_fixture = 100Ohm
C_fixture = 0F
|   Time   V(typ)   V(min)   V(max)
0s        3.3V       3V         3.6V
1.533ns   3.325V     3.009V     3.6V
1.8ns     3.213V     3.018V     3.043V
2.153ns   2.664V     2.978V     2.154V
2.452ns   2.186V     2.748V     1.569V
2.901ns   1.61V      2.291V     1.113V
3.297ns   1.275V     1.953V     933.4mV
3.927ns   1.009V     1.519V     908.9mV
5.133ns   973.2mV    1.08V      903.1mV
20ns      965.8mV    1.03V      901.3mV
[Rising Waveform]
V_fixture = 0V
V_fixture_min = 0V
V_fixture_max = 0V
R_fixture = 100Ohm
C_fixture = 0F
|   Time   V(typ)   V(min)   V(max)
0s        106.3uV    105.8uV    101.2uV
1.321ns   -45.26mV   -25.33mV   -48.15mV
1.589ns   -15.64mV   -45.29mV   37.91mV
1.845ns   122.8mV    -16.84mV   776.5mV
2.317ns   1.228V     99.62mV    2.169V
2.562ns   1.735V     417.1mV    2.421V
2.781ns   1.983V     766.1mV    2.479V
3.404ns   2.113V     1.526V     2.507V
4.227ns   2.135V     1.749V     2.512V
20ns      2.154V     1.805V     2.523V
[Rising Waveform]
V_fixture = 3.3V
V_fixture_min = 3V
V_fixture_max = 3.6V
R_fixture = 100Ohm
C_fixture = 0F
|   Time   V(typ)   V(min)   V(max)
0s        965.8mV    1.03V      901.3mV
1.172ns   964mV      1.029V     908.9mV
1.303ns   1.211V     1.062V     1.36V
1.583ns   2.092V     1.789V     2.349V
1.824ns   2.584V     2.266V     3.093V
2.028ns   2.963V     2.516V     3.463V
2.276ns   3.22V      2.711V     3.569V
2.665ns   3.281V     2.935V     3.592V
3.368ns   3.295V     2.991V     3.596V
20ns      3.3V       3V         3.6V
[Falling Waveform]
|Gnd
V_fixture = 0V
V_fixture_min = 0V
V_fixture_max = 0V
R_fixture = 100Ohm
C_fixture = 0F
|   Time   V(typ)   V(min)   V(max)
0s        2.149V     1.794V     2.521V
1.463ns   2.133V     1.796V     2.458V
1.708ns   1.94V      1.758V     1.82V
1.953ns   1.381V     1.644V     825.7mV
2.074ns   1.029V     1.577V     487.2mV
2.334ns   416.2mV    1.223V     180.6mV
2.659ns   146.3mV    605.7mV    18.88mV
3ns       22.17mV    223.7mV    4.056mV
3.644ns   3.788mV    17.75mV    1.653mV
20ns      106.1uV    105.7uV    101.1uV
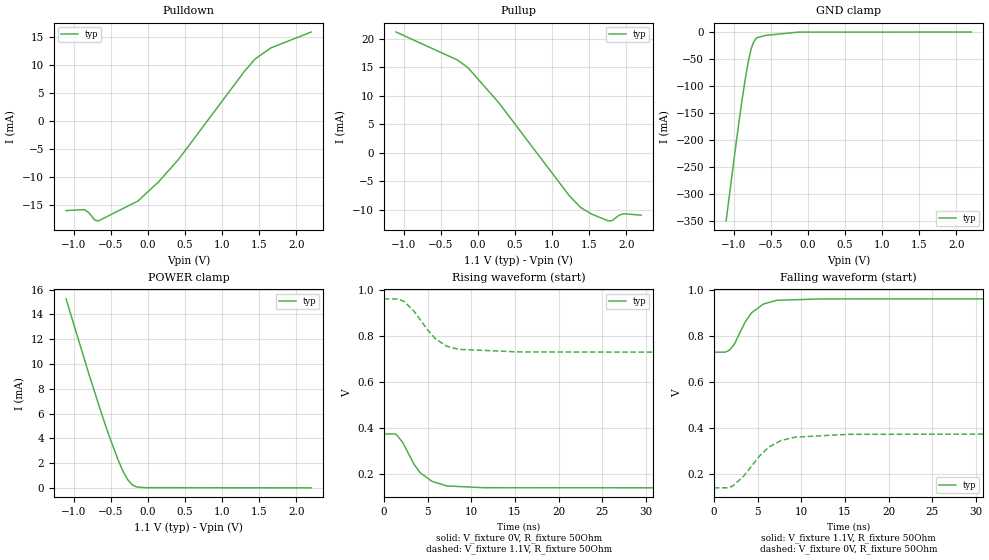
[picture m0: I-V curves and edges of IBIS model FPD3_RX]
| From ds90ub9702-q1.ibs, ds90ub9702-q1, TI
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|  FPD3_RX
[Model]   FPD3_RX
Model_type   I/O
Polarity   Non-Inverting
Enable   Active-High
Vinl = 0
Vinh = 0
Vmeas = 0.55
Vref = 0.55
Cref = 0.02pF
Rref = 50
|   typ   min   max
C_comp   1.27pF   1.06pF   0.87pF
[Voltage Range]   1.1   NA   NA
[Temperature Range]   27   NA   NA
[Pullup Reference]   1.1   NA   NA
[Pulldown Reference]   0   NA   NA
[Power Clamp Reference]   1.1   NA   NA
[GND Clamp Reference]   0   NA   NA
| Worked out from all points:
|   slope of the pulldown table from 0 to 0.165 V, typ, clamps not added: 76.1 ohm
|   slope of the pullup table from 0 to 0.165 V, typ, clamps not added: 66.4 ohm
|   GND clamp passes 1 mA (typ) near -0.24 V on its own axis
|   POWER clamp passes 1 mA (typ) near -0.30 V on its own axis
|   falling waveform, V_fixture 1.1V, R_fixture 50Ohm: 20-80 % time 2.2ns typ, NA min, NA max; typ from 0.731 V to 0.963 V
|   rising waveform, V_fixture 0V, R_fixture 50Ohm: 20-80 % time 2.42ns typ, NA min, NA max; typ from 0.374 V to 0.14 V
|   rising waveform, V_fixture 1.1V, R_fixture 50Ohm: 20-80 % time 3ns typ, NA min, NA max; typ from 0.963 V to 0.731 V
|   falling waveform, V_fixture 0V, R_fixture 50Ohm: 20-80 % time 3.37ns typ, NA min, NA max; typ from 0.14 V to 0.374 V
[Pulldown]
|   Voltage   I(typ)   I(min)   I(max)
-1.1V     -16.03mA   NA         NA
-855.8mV  -15.86mA   NA         NA
-799.7mV  -16.32mA   NA         NA
-713.9mV  -17.71mA   NA         NA
-667.7mV  -17.9mA    NA         NA
-133.1mV  -14.32mA   NA         NA
144.1mV   -10.9mA    NA         NA
418mV     -6.795mA   NA         NA
1.299V    8.887mA    NA         NA
1.444V    11.13mA    NA         NA
1.655V    13.12mA    NA         NA
2.2V      15.98mA    NA         NA
[GND Clamp]
|   Voltage   I(typ)   I(min)   I(max)
-1.1V     -350mA     NA         NA
-968mV    -208.5mA   NA         NA
-918.5mV  -158.2mA   NA         NA
-875.6mV  -117mA     NA         NA
-836mV    -81.88mA   NA         NA
-799.7mV  -53.73mA   NA         NA
-763.4mV  -31.6mA    NA         NA
-727.1mV  -17.58mA   NA         NA
-687.5mV  -10.66mA   NA         NA
-572mV    -6.281mA   NA         NA
-129.8mV  -164.5uA   NA         NA
2.2V      0A         NA         NA
[Pullup]
|   Voltage   I(typ)   I(min)   I(max)
-1.1V     21.2mA     NA         NA
-275mV    16.3mA     NA         NA
-133.1mV  14.96mA    NA         NA
279.4mV   8.855mA    NA         NA
1.23V     -7.476mA   NA         NA
1.385V    -9.581mA   NA         NA
1.533V    -10.74mA   NA         NA
1.764V    -11.95mA   NA         NA
1.811V    -11.87mA   NA         NA
1.9V      -10.96mA   NA         NA
1.959V    -10.68mA   NA         NA
2.2V      -10.92mA   NA         NA
[POWER Clamp]
|   Voltage   I(typ)   I(min)   I(max)
-1.1V     15.26mA    NA         NA
-793.1mV  9.194mA    NA         NA
-621.5mV  5.98mA     NA         NA
-515.9mV  4.118mA    NA         NA
-397.1mV  2.216mA    NA         NA
-331.1mV  1.316mA    NA         NA
-268.4mV  644.1uA    NA         NA
-205.7mV  229.8uA    NA         NA
-149.6mV  73.87uA    NA         NA
-40.7mV   14.59uA    NA         NA
2.2V      0A         NA         NA
[Ramp]
R_load = 50
|   typ   min   max
dV/dt_r   0.140947/2.41624e-09  NA   NA
dV/dt_f   0.139525/2.19661e-09  NA   NA
[Falling Waveform]
V_fixture = 1.1V
R_fixture = 50Ohm
C_fixture = 0F
|   Time   V(typ)   V(min)   V(max)
0s        730.9mV    NA         NA
1.296ns   731mV      NA         NA
1.787ns   739.6mV    NA         NA
2.329ns   764.3mV    NA         NA
3.56ns    861mV      NA         NA
4.321ns   903.1mV    NA         NA
5.695ns   941.2mV    NA         NA
7.201ns   957.1mV    NA         NA
12.08ns   963mV      NA         NA
40ns      963.4mV    NA         NA
[Rising Waveform]
V_fixture = 0V
R_fixture = 50Ohm
C_fixture = 0F
|   Time   V(typ)   V(min)   V(max)
0s        374.5mV    NA         NA
1.283ns   374.5mV    NA         NA
1.501ns   369.6mV    NA         NA
2.131ns   339.2mV    NA         NA
3.45ns    243.1mV    NA         NA
4.139ns   206.2mV    NA         NA
5.516ns   168mV      NA         NA
7.201ns   147.9mV    NA         NA
11.41ns   140.2mV    NA         NA
40ns      139.6mV    NA         NA
[Rising Waveform]
V_fixture = 1.1V
R_fixture = 50Ohm
C_fixture = 0F
|   Time   V(typ)   V(min)   V(max)
0s        963.5mV    NA         NA
1.594ns   962.8mV    NA         NA
2.329ns   952.3mV    NA         NA
3.45ns    909.7mV    NA         NA
5.049ns   826.3mV    NA         NA
5.916ns   789.2mV    NA         NA
7.201ns   756.9mV    NA         NA
8.547ns   743.4mV    NA         NA
15.43ns   732.1mV    NA         NA
40ns      730.9mV    NA         NA
[Falling Waveform]
|Gnd
V_fixture = 0V
R_fixture = 50Ohm
C_fixture = 0F
|   Time   V(typ)   V(min)   V(max)
0s        139.6mV    NA         NA
1.541ns   139.9mV    NA         NA
2.131ns   146.5mV    NA         NA
3.45ns    192.2mV    NA         NA
5.27ns    280.2mV    NA         NA
6.275ns   316.9mV    NA         NA
7.673ns   345.9mV    NA         NA
9.3ns     360.6mV    NA         NA
15.43ns   372.9mV    NA         NA
40ns      374.5mV    NA         NA
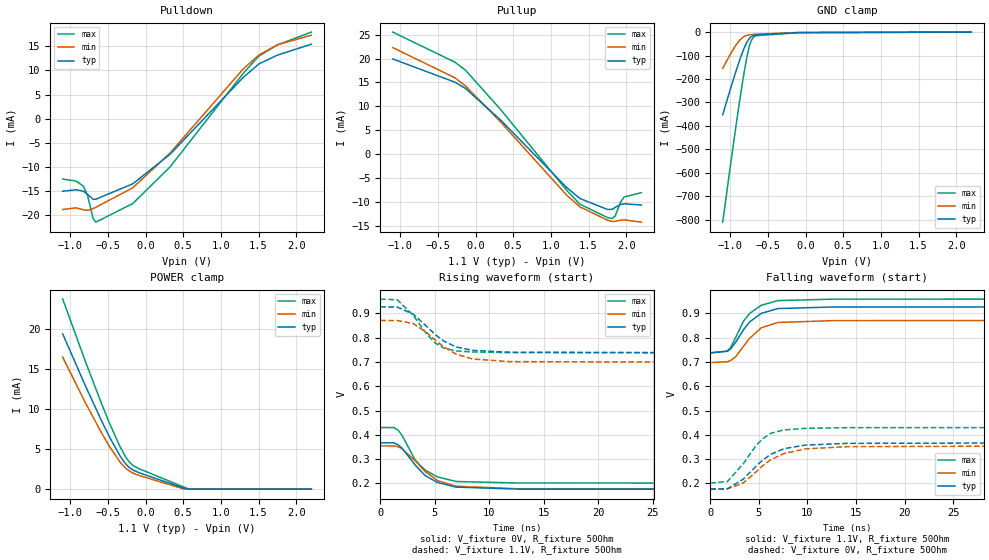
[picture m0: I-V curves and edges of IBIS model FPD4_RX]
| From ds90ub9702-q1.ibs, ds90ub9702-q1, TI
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|  FPD4_RX
[Model]   FPD4_RX
Model_type   I/O
Polarity   Non-Inverting
Enable   Active-High
Vinl = 0
Vinh = 0
Vmeas = 0.55
Vref = 0.55
Cref = 0.02pF
Rref = 50
|   typ   min   max
C_comp   1.27pF   1.06pF   0.87pF
[Voltage Range]   1.1   1.045   1.155
[Temperature Range]   27   105   -40
[Pullup Reference]   1.1   1.045   1.155
[Pulldown Reference]   0   -0   0
[Power Clamp Reference]   1.1   1.045   1.155
[GND Clamp Reference]   0   0   0
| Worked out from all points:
|   slope of the pulldown table from 0 to 0.165 V, typ, clamps not added: 79.3 ohm
|   slope of the pullup table from 0 to 0.165 V, typ, clamps not added: 70.1 ohm
|   falling waveform, V_fixture 1.1V, R_fixture 50Ohm: 20-80 % time 2.24ns typ, 2.24ns min, 2.07ns max; typ from 0.737 V to 0.926 V
|   rising waveform, V_fixture 0V, R_fixture 50Ohm: 20-80 % time 2.43ns typ, 2.55ns min, 2.2ns max; typ from 0.367 V to 0.177 V
|   rising waveform, V_fixture 1.1V, R_fixture 50Ohm: 20-80 % time 3.02ns typ, 3.12ns min, 2.35ns max; typ from 0.927 V to 0.737 V
|   falling waveform, V_fixture 0V, R_fixture 50Ohm: 20-80 % time 3.36ns typ, 3.52ns min, 2.69ns max; typ from 0.176 V to 0.367 V
[Pulldown]
|   Voltage   I(typ)   I(min)   I(max)
-1.1V     -15.03mA   -18.83mA   -12.52mA
-921.8mV  -14.74mA   -18.48mA   -12.93mA
-826.1mV  -15.02mA   -18.89mA   -13.98mA
-770mV    -15.69mA   -18.99mA   -15.89mA
-697.4mV  -16.69mA   -18.64mA   -20.64mA
-661.1mV  -16.7mA    -18.38mA   -21.46mA
-169.4mV  -13.5mA    -14.32mA   -17.58mA
325.6mV   -7.375mA   -7.108mA   -9.987mA
1.296V    8.567mA    10.32mA    9.407mA
1.504V    11.35mA    13.2mA     12.99mA
1.748V    13.17mA    15.32mA    15.28mA
2.2V      15.45mA    17.32mA    17.96mA
[GND Clamp]
|   Voltage   I(typ)   I(min)   I(max)
-1.1V     -353.1mA   -154.7mA   -811.3mA
-1.004V   -249.5mA   -97.33mA   -584.5mA
-928.4mV  -171mA     -57.24mA   -410.4mA
-869mV    -113.8mA   -32.56mA   -280.2mA
-816.2mV  -68.89mA   -18.73mA   -172.9mA
-783.2mV  -45.81mA   -14.18mA   -113.6mA
-750.2mV  -28.64mA   -11.74mA   -65.06mA
-727.1mV  -20.77mA   -10.72mA   -40.8mA
-697.4mV  -15.04mA   -9.836mA   -23.17mA
-657.8mV  -11.81mA   -8.974mA   -15.34mA
-103.4mV  -2.163mA   -1.785mA   -2.749mA
2.2V      0A         0A         0A
[Pullup]
|   Voltage   I(typ)   I(min)   I(max)
-1.1V     19.92mA    22.3mA     25.54mA
-275mV    15.06mA    15.98mA    19.25mA
-136.4mV  13.78mA    14.31mA    17.6mA
325.6mV   7.243mA    6.846mA    9.466mA
1.207V    -6.954mA   -8.544mA   -7.527mA
1.385V    -9.294mA   -11.03mA   -10.47mA
1.754V    -11.59mA   -13.84mA   -13.29mA
1.817V    -11.52mA   -14.08mA   -13.48mA
1.853V    -11.15mA   -14.06mA   -12.94mA
1.923V    -10.54mA   -13.83mA   -10.08mA
1.972V    -10.39mA   -13.74mA   -8.966mA
2.2V      -10.65mA   -14.24mA   -8.057mA
[POWER Clamp]
|   Voltage   I(typ)   I(min)   I(max)
-1.1V     19.38mA    16.48mA    23.73mA
-799.7mV  12.92mA    10.8mA     15.96mA
-581.9mV  8.479mA    6.982mA    10.61mA
-473mV    6.405mA    5.235mA    8.095mA
-337.7mV  4.123mA    3.371mA    5.276mA
-275mV    3.28mA     2.713mA    4.184mA
-222.2mV  2.749mA    2.301mA    3.459mA
-169.4mV  2.395mA    2.013mA    2.975mA
-86.9mV   2.052mA    1.71mA     2.555mA
517mV     100.9uA    5.109uA    228.8uA
576.4mV   0A         0A         991.6nA
2.2V      0A         0A         0A
[Ramp]
R_load = 50
|   typ   min   max
dV/dt_r   0.114429/2.42559e-09   0.106147/2.55473e-09   0.137141/2.20382e-09
dV/dt_f   0.113711/2.24222e-09   0.103884/2.24059e-09   0.132736/2.0692e-09
[Falling Waveform]
V_fixture = 1.1V
V_fixture_min = 1.045V
V_fixture_max = 1.155V
R_fixture = 50Ohm
C_fixture = 0F
|   Time   V(typ)   V(min)   V(max)
0s        736.9mV    697.4mV    737.4mV
1.762ns   743.6mV    700.7mV    745.1mV
2.125ns   754.8mV    706.3mV    761.2mV
2.62ns    781.8mV    722.1mV    801.3mV
3.42ns    832.3mV    764.3mV    867.9mV
4.032ns   864.1mV    796.6mV    899.2mV
5.243ns   899.7mV    840.4mV    933.1mV
6.957ns   919.6mV    862.4mV    952.4mV
12.55ns   926mV      869.9mV    958.3mV
40ns      926.4mV    870.5mV    958.7mV
[Rising Waveform]
V_fixture = 0V
V_fixture_min = 0V
V_fixture_max = 0V
R_fixture = 50Ohm
C_fixture = 0F
|   Time   V(typ)   V(min)   V(max)
0s        367.2mV    354.6mV    430.1mV
1.235ns   367.2mV    354.5mV    430mV
1.649ns   358.8mV    350.8mV    418.8mV
2.005ns   344.6mV    342.7mV    397.5mV
3.208ns   275.6mV    293mV      296mV
4.12ns    232.4mV    249.1mV    254.7mV
5.243ns   204.1mV    212mV      227mV
6.957ns   184.9mV    188.6mV    208.1mV
12.55ns   176.9mV    178.3mV    201.9mV
40ns      176.5mV    177.6mV    201.5mV
[Rising Waveform]
V_fixture = 1.1V
V_fixture_min = 1.045V
V_fixture_max = 1.155V
R_fixture = 50Ohm
C_fixture = 0F
|   Time   V(typ)   V(min)   V(max)
0s        926.5mV    870.6mV    958.8mV
1.557ns   925.9mV    870.3mV    955.8mV
3.002ns   897.1mV    858.7mV    893.2mV
4.277ns   845.5mV    820.4mV    813.9mV
5.071ns   811.6mV    789.1mV    777.1mV
5.824ns   786mV      762mV      757.3mV
6.957ns   761.8mV    732.3mV    745.5mV
8.47ns    747.6mV    712.2mV    741mV
11.88ns   740.1mV    701.4mV    738.4mV
40ns      737mV      697.4mV    737.5mV
[Falling Waveform]
|Gnd
V_fixture = 0V
V_fixture_min = 0V
V_fixture_max = 0V
R_fixture = 50Ohm
C_fixture = 0F
|   Time   V(typ)   V(min)   V(max)
0s        176.5mV    177.6mV    201.5mV
1.762ns   178mV      178.1mV    208mV
3.358ns   216.7mV    200.8mV    279.3mV
4.684ns   269.7mV    246.5mV    354.5mV
5.394ns   296.4mV    273mV      384.5mV
6.235ns   320.3mV    297.8mV    406.4mV
7.568ns   342.9mV    323mV      420.3mV
9.779ns   357.8mV    342.2mV    426.8mV
14.07ns   365mV      351.4mV    429.5mV
40ns      367.2mV    354.5mV    430mV
